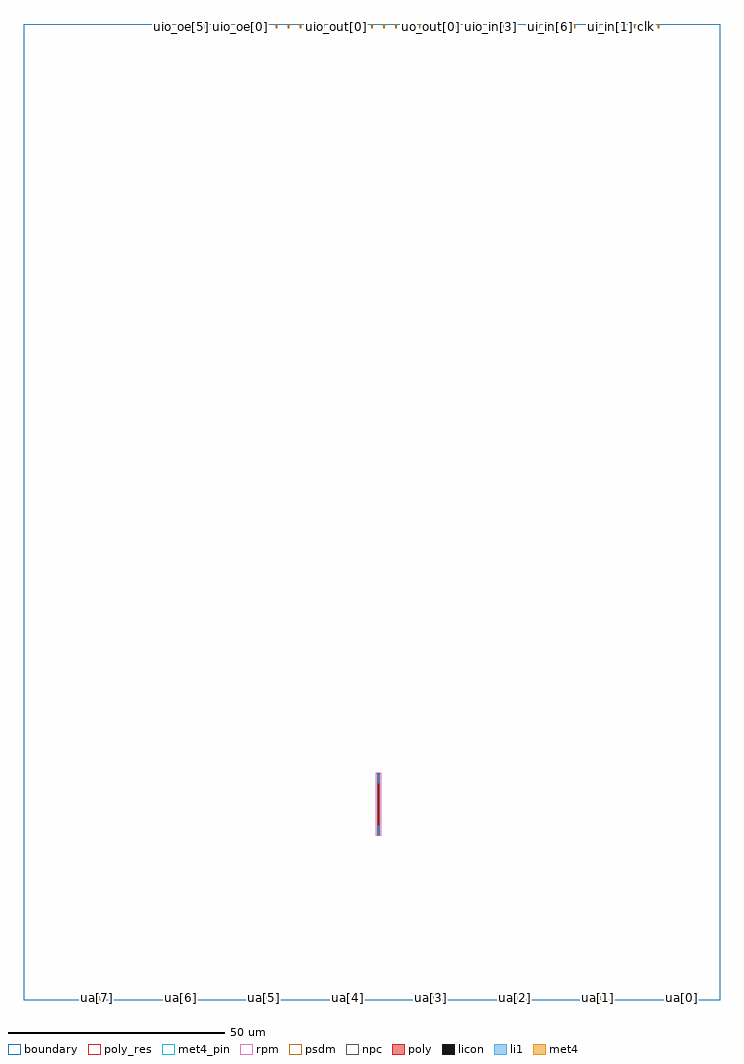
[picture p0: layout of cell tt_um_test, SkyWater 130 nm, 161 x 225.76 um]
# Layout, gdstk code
import gdstk
lib = gdstk.Library(unit=1e-6, precision=1e-09)
def R(c, l, rs):  # rectangles x0, y0, x1, y1
    for r in rs: c.add(gdstk.rectangle(r[:2], r[2:], *l))
def A(c, l, x, y, w, h, nx, ny, dx, dy):  # array of equal rectangles
    R(c, l, [(x+i*dx, y+j*dy, x+i*dx+w, y+j*dy+h) for i in range(nx) for j in range(ny)])
poly_res = (66, 13)
poly = (66, 20)
licon = (66, 44)
li1 = (67, 20)
met4_pin = (71, 16)
met4 = (71, 20)
rpm = (86, 20)
psdm = (94, 20)
npc = (95, 20)
boundary = (235, 4)

sky130_fd_pr__res_high_p = lib.new_cell('sky130_fd_pr__res_high_po_0p35_K6VBXT')
R(sky130_fd_pr__res_high_p, poly_res, [(-0.175,-5,0.175,5)])
R(sky130_fd_pr__res_high_p, poly, [(-0.175,-7.08,0.175,7.08)])
R(sky130_fd_pr__res_high_p, licon, [(-0.095,-7,0.095,-5), (-0.095,5,0.095,7)])
R(sky130_fd_pr__res_high_p, li1, [(-0.175,-7.08,0.175,-4.92), (-0.175,4.92,0.175,7.08)])
R(sky130_fd_pr__res_high_p, rpm, [(-0.635,-7.28,0.635,7.28)])
R(sky130_fd_pr__res_high_p, psdm, [(-0.285,-7.19,0.285,7.19)])
R(sky130_fd_pr__res_high_p, npc, [(-0.27,-7.175,0.27,7.175)])

res10u = lib.new_cell('res10u')
res10u.add(gdstk.Reference(sky130_fd_pr__res_high_p, (0.225,7.08)))

tt_um_test = lib.new_cell('tt_um_test')
A(tt_um_test, met4_pin, 16.57, 0, 0.9, 1, 8, 1, 19.32, 0)
A(tt_um_test, met4_pin, 30.67, 224.76, 0.3, 1, 43, 1, 2.76, 0)
A(tt_um_test, met4, 16.57, 0, 0.9, 1, 8, 1, 19.32, 0)
A(tt_um_test, met4, 30.67, 224.76, 0.3, 1, 43, 1, 2.76, 0)
R(tt_um_test, boundary, [(0,0,161,225.76)])
tt_um_test.add(gdstk.Reference(res10u, (81.76,38.18)))
tt_um_test.add(gdstk.Label('clk', (143.98,225.26), layer=71, texttype=5))
tt_um_test.add(gdstk.Label('ena', (146.74,225.26), layer=71, texttype=5))
tt_um_test.add(gdstk.Label('rst_n', (141.22,225.26), layer=71, texttype=5))
tt_um_test.add(gdstk.Label('ua[0]', (152.26,0.5), layer=71, texttype=5))
tt_um_test.add(gdstk.Label('ua[1]', (132.94,0.5), layer=71, texttype=5))
tt_um_test.add(gdstk.Label('ua[2]', (113.62,0.5), layer=71, texttype=5))
tt_um_test.add(gdstk.Label('ua[3]', (94.3,0.5), layer=71, texttype=5))
tt_um_test.add(gdstk.Label('ua[4]', (74.98,0.5), layer=71, texttype=5))
tt_um_test.add(gdstk.Label('ua[5]', (55.66,0.5), layer=71, texttype=5))
tt_um_test.add(gdstk.Label('ua[6]', (36.34,0.5), layer=71, texttype=5))
tt_um_test.add(gdstk.Label('ua[7]', (17.02,0.5), layer=71, texttype=5))
tt_um_test.add(gdstk.Label('ui_in[0]', (138.46,225.26), layer=71, texttype=5))
tt_um_test.add(gdstk.Label('ui_in[1]', (135.7,225.26), layer=71, texttype=5))
tt_um_test.add(gdstk.Label('ui_in[2]', (132.94,225.26), layer=71, texttype=5))
tt_um_test.add(gdstk.Label('ui_in[3]', (130.18,225.26), layer=71, texttype=5))
tt_um_test.add(gdstk.Label('ui_in[4]', (127.42,225.26), layer=71, texttype=5))
tt_um_test.add(gdstk.Label('ui_in[5]', (124.66,225.26), layer=71, texttype=5))
tt_um_test.add(gdstk.Label('ui_in[6]', (121.9,225.26), layer=71, texttype=5))
tt_um_test.add(gdstk.Label('ui_in[7]', (119.14,225.26), layer=71, texttype=5))
tt_um_test.add(gdstk.Label('uio_in[0]', (116.38,225.26), layer=71, texttype=5))
tt_um_test.add(gdstk.Label('uio_in[1]', (113.62,225.26), layer=71, texttype=5))
tt_um_test.add(gdstk.Label('uio_in[2]', (110.86,225.26), layer=71, texttype=5))
tt_um_test.add(gdstk.Label('uio_in[3]', (108.1,225.26), layer=71, texttype=5))
tt_um_test.add(gdstk.Label('uio_in[4]', (105.34,225.26), layer=71, texttype=5))
tt_um_test.add(gdstk.Label('uio_in[5]', (102.58,225.26), layer=71, texttype=5))
tt_um_test.add(gdstk.Label('uio_in[6]', (99.82,225.26), layer=71, texttype=5))
tt_um_test.add(gdstk.Label('uio_in[7]', (97.06,225.26), layer=71, texttype=5))
tt_um_test.add(gdstk.Label('uio_oe[0]', (50.14,225.26), layer=71, texttype=5))
tt_um_test.add(gdstk.Label('uio_oe[1]', (47.38,225.26), layer=71, texttype=5))
tt_um_test.add(gdstk.Label('uio_oe[2]', (44.62,225.26), layer=71, texttype=5))
tt_um_test.add(gdstk.Label('uio_oe[3]', (41.86,225.26), layer=71, texttype=5))
tt_um_test.add(gdstk.Label('uio_oe[4]', (39.1,225.26), layer=71, texttype=5))
tt_um_test.add(gdstk.Label('uio_oe[5]', (36.34,225.26), layer=71, texttype=5))
tt_um_test.add(gdstk.Label('uio_oe[6]', (33.58,225.26), layer=71, texttype=5))
tt_um_test.add(gdstk.Label('uio_oe[7]', (30.82,225.26), layer=71, texttype=5))
tt_um_test.add(gdstk.Label('uio_out[0]', (72.22,225.26), layer=71, texttype=5))
tt_um_test.add(gdstk.Label('uio_out[1]', (69.46,225.26), layer=71, texttype=5))
tt_um_test.add(gdstk.Label('uio_out[2]', (66.7,225.26), layer=71, texttype=5))
tt_um_test.add(gdstk.Label('uio_out[3]', (63.94,225.26), layer=71, texttype=5))
tt_um_test.add(gdstk.Label('uio_out[4]', (61.18,225.26), layer=71, texttype=5))
tt_um_test.add(gdstk.Label('uio_out[5]', (58.42,225.26), layer=71, texttype=5))
tt_um_test.add(gdstk.Label('uio_out[6]', (55.66,225.26), layer=71, texttype=5))
tt_um_test.add(gdstk.Label('uio_out[7]', (52.9,225.26), layer=71, texttype=5))
tt_um_test.add(gdstk.Label('uo_out[0]', (94.3,225.26), layer=71, texttype=5))
tt_um_test.add(gdstk.Label('uo_out[1]', (91.54,225.26), layer=71, texttype=5))
tt_um_test.add(gdstk.Label('uo_out[2]', (88.78,225.26), layer=71, texttype=5))
tt_um_test.add(gdstk.Label('uo_out[3]', (86.02,225.26), layer=71, texttype=5))
tt_um_test.add(gdstk.Label('uo_out[4]', (83.26,225.26), layer=71, texttype=5))
tt_um_test.add(gdstk.Label('uo_out[5]', (80.5,225.26), layer=71, texttype=5))
tt_um_test.add(gdstk.Label('uo_out[6]', (77.74,225.26), layer=71, texttype=5))
tt_um_test.add(gdstk.Label('uo_out[7]', (74.98,225.26), layer=71, texttype=5))

lib.write_gds('tt_um_test.gds')
